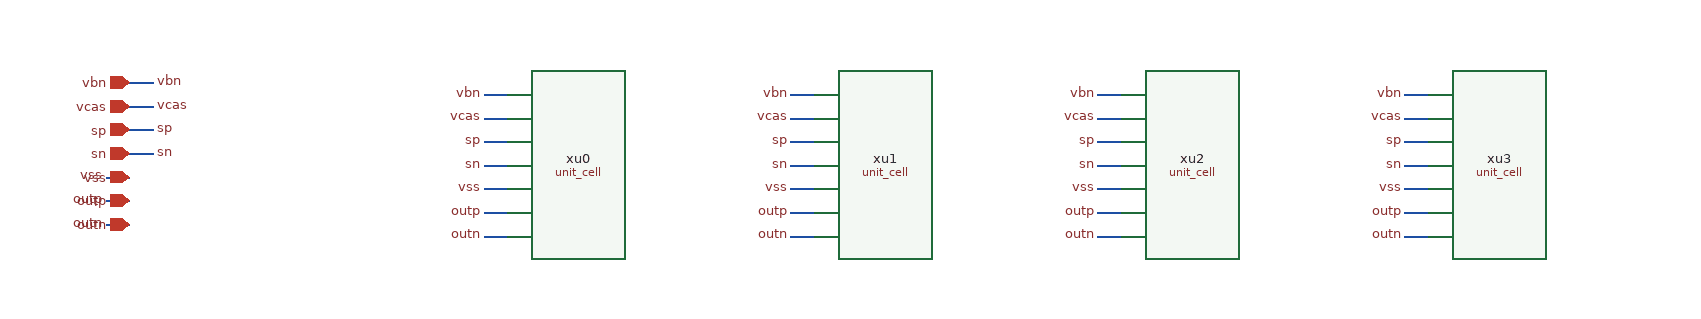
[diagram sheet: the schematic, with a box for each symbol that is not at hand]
v {xschem version=3.4.4 file_version=1.2
}
G {}
V {}
S {}
E {}
C {unit_cell.sym} 0 0 0 0 {name=xu0}
N -80 10 -100 10 {}
C {devices/lab_pin.sym} -100 10 0 0 {name=l1 sig_type=std_logic lab=vbn}
N -80 30 -100 30 {}
C {devices/lab_pin.sym} -100 30 0 0 {name=l2 sig_type=std_logic lab=vcas}
N -80 50 -100 50 {}
C {devices/lab_pin.sym} -100 50 0 0 {name=l3 sig_type=std_logic lab=sp}
N -80 70 -100 70 {}
C {devices/lab_pin.sym} -100 70 0 0 {name=l4 sig_type=std_logic lab=sn}
N -80 90 -100 90 {}
C {devices/lab_pin.sym} -100 90 0 0 {name=l5 sig_type=std_logic lab=vss}
N -80 110 -100 110 {}
C {devices/lab_pin.sym} -100 110 0 0 {name=l6 sig_type=std_logic lab=outp}
N -80 130 -100 130 {}
C {devices/lab_pin.sym} -100 130 0 0 {name=l7 sig_type=std_logic lab=outn}
C {unit_cell.sym} 260 0 0 0 {name=xu1}
N 180 10 160 10 {}
C {devices/lab_pin.sym} 160 10 0 0 {name=l8 sig_type=std_logic lab=vbn}
N 180 30 160 30 {}
C {devices/lab_pin.sym} 160 30 0 0 {name=l9 sig_type=std_logic lab=vcas}
N 180 50 160 50 {}
C {devices/lab_pin.sym} 160 50 0 0 {name=l10 sig_type=std_logic lab=sp}
N 180 70 160 70 {}
C {devices/lab_pin.sym} 160 70 0 0 {name=l11 sig_type=std_logic lab=sn}
N 180 90 160 90 {}
C {devices/lab_pin.sym} 160 90 0 0 {name=l12 sig_type=std_logic lab=vss}
N 180 110 160 110 {}
C {devices/lab_pin.sym} 160 110 0 0 {name=l13 sig_type=std_logic lab=outp}
N 180 130 160 130 {}
C {devices/lab_pin.sym} 160 130 0 0 {name=l14 sig_type=std_logic lab=outn}
C {unit_cell.sym} 520 0 0 0 {name=xu2}
N 440 10 420 10 {}
C {devices/lab_pin.sym} 420 10 0 0 {name=l15 sig_type=std_logic lab=vbn}
N 440 30 420 30 {}
C {devices/lab_pin.sym} 420 30 0 0 {name=l16 sig_type=std_logic lab=vcas}
N 440 50 420 50 {}
C {devices/lab_pin.sym} 420 50 0 0 {name=l17 sig_type=std_logic lab=sp}
N 440 70 420 70 {}
C {devices/lab_pin.sym} 420 70 0 0 {name=l18 sig_type=std_logic lab=sn}
N 440 90 420 90 {}
C {devices/lab_pin.sym} 420 90 0 0 {name=l19 sig_type=std_logic lab=vss}
N 440 110 420 110 {}
C {devices/lab_pin.sym} 420 110 0 0 {name=l20 sig_type=std_logic lab=outp}
N 440 130 420 130 {}
C {devices/lab_pin.sym} 420 130 0 0 {name=l21 sig_type=std_logic lab=outn}
C {unit_cell.sym} 780 0 0 0 {name=xu3}
N 700 10 680 10 {}
C {devices/lab_pin.sym} 680 10 0 0 {name=l22 sig_type=std_logic lab=vbn}
N 700 30 680 30 {}
C {devices/lab_pin.sym} 680 30 0 0 {name=l23 sig_type=std_logic lab=vcas}
N 700 50 680 50 {}
C {devices/lab_pin.sym} 680 50 0 0 {name=l24 sig_type=std_logic lab=sp}
N 700 70 680 70 {}
C {devices/lab_pin.sym} 680 70 0 0 {name=l25 sig_type=std_logic lab=sn}
N 700 90 680 90 {}
C {devices/lab_pin.sym} 680 90 0 0 {name=l26 sig_type=std_logic lab=vss}
N 700 110 680 110 {}
C {devices/lab_pin.sym} 680 110 0 0 {name=l27 sig_type=std_logic lab=outp}
N 700 130 680 130 {}
C {devices/lab_pin.sym} 680 130 0 0 {name=l28 sig_type=std_logic lab=outn}
C {devices/ipin.sym} -400 0 0 0 {name=p29 lab=vbn}
N -400 0 -380 0 {}
C {devices/lab_pin.sym} -380 0 2 0 {name=l30 sig_type=std_logic lab=vbn}
C {devices/ipin.sym} -400 20 0 0 {name=p31 lab=vcas}
N -400 20 -380 20 {}
C {devices/lab_pin.sym} -380 20 2 0 {name=l32 sig_type=std_logic lab=vcas}
C {devices/ipin.sym} -400 40 0 0 {name=p33 lab=sp}
N -400 40 -380 40 {}
C {devices/lab_pin.sym} -380 40 2 0 {name=l34 sig_type=std_logic lab=sp}
C {devices/ipin.sym} -400 60 0 0 {name=p35 lab=sn}
N -400 60 -380 60 {}
C {devices/lab_pin.sym} -380 60 2 0 {name=l36 sig_type=std_logic lab=sn}
C {devices/iopin.sym} -400 80 0 0 {name=p37 lab=vss}
N -400 80 -420 80 {}
C {devices/lab_pin.sym} -420 80 0 0 {name=l38 sig_type=std_logic lab=vss}
C {devices/iopin.sym} -400 100 0 0 {name=p39 lab=outp}
N -400 100 -420 100 {}
C {devices/lab_pin.sym} -420 100 0 0 {name=l40 sig_type=std_logic lab=outp}
C {devices/iopin.sym} -400 120 0 0 {name=p41 lab=outn}
N -400 120 -420 120 {}
C {devices/lab_pin.sym} -420 120 0 0 {name=l42 sig_type=std_logic lab=outn}
